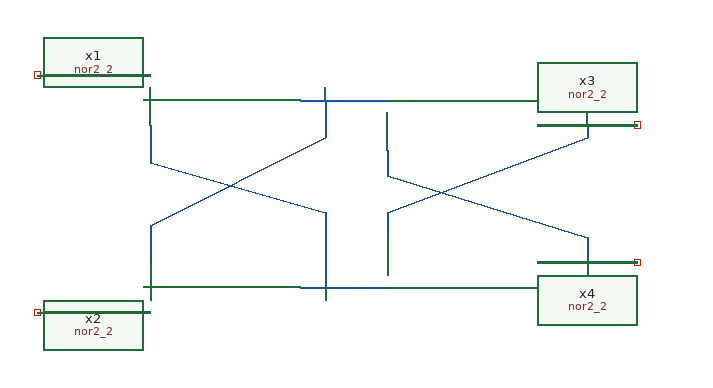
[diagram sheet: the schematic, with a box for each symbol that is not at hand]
v {xschem version=3.4.4 file_version=1.2
}
G {}
K {}
V {}
S {}
E {}
B 5 297.5 -472.5 302.5 -467.5 {name=OUT+
dir=inout}
B 5 297.5 -282.5 302.5 -277.5 {name=XXX
dir=inout}
B 5 777.5 -432.5 782.5 -427.5 {name=XXX
dir=inout}
B 5 777.5 -322.5 782.5 -317.5 {name=XXX
dir=inout}
N 510 -450 580 -450 {}
N 300 -470 390 -470 {}
N 510 -300 580 -300 {}
N 700 -430 780 -430 {}
N 700 -320 780 -320 {}
N 580 -410 580 -390 {}
N 580 -390 740 -340 {}
N 740 -340 740 -320 {}
N 580 -360 580 -340 {}
N 580 -360 740 -420 {}
N 740 -430 740 -420 {}
N 390 -350 390 -320 {}
N 390 -350 530 -420 {}
N 530 -450 530 -420 {}
N 390 -430 390 -400 {}
N 390 -400 530 -360 {}
N 530 -360 530 -300 {}
N 300 -280 390 -280 {}
C {xschem_sky130/sky130_stdcells/nor2_2.sym} 450 -450 0 0 {name=x1 VGND=VGND VNB=VNB VPB=VPB VPWR=VPWR prefix=sky130_fd_sc_hd__ }
C {xschem_sky130/sky130_stdcells/nor2_2.sym} 450 -300 0 0 {name=x2 VGND=VGND VNB=VNB VPB=VPB VPWR=VPWR prefix=sky130_fd_sc_hd__ }
C {xschem_sky130/sky130_stdcells/nor2_2.sym} 640 -430 0 0 {name=x3 VGND=VGND VNB=VNB VPB=VPB VPWR=VPWR prefix=sky130_fd_sc_hd__ }
C {xschem_sky130/sky130_stdcells/nor2_2.sym} 640 -320 0 0 {name=x4 VGND=VGND VNB=VNB VPB=VPB VPWR=VPWR prefix=sky130_fd_sc_hd__ }
